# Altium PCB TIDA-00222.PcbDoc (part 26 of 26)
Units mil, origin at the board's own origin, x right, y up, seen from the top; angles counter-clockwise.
Board outline 5049.4 x 2450.97 mil, 2 copper layers (Top Layer, Bottom Layer), stack 62 mil thick; 216 components, 154 nets, 612 pads, 100 vias.

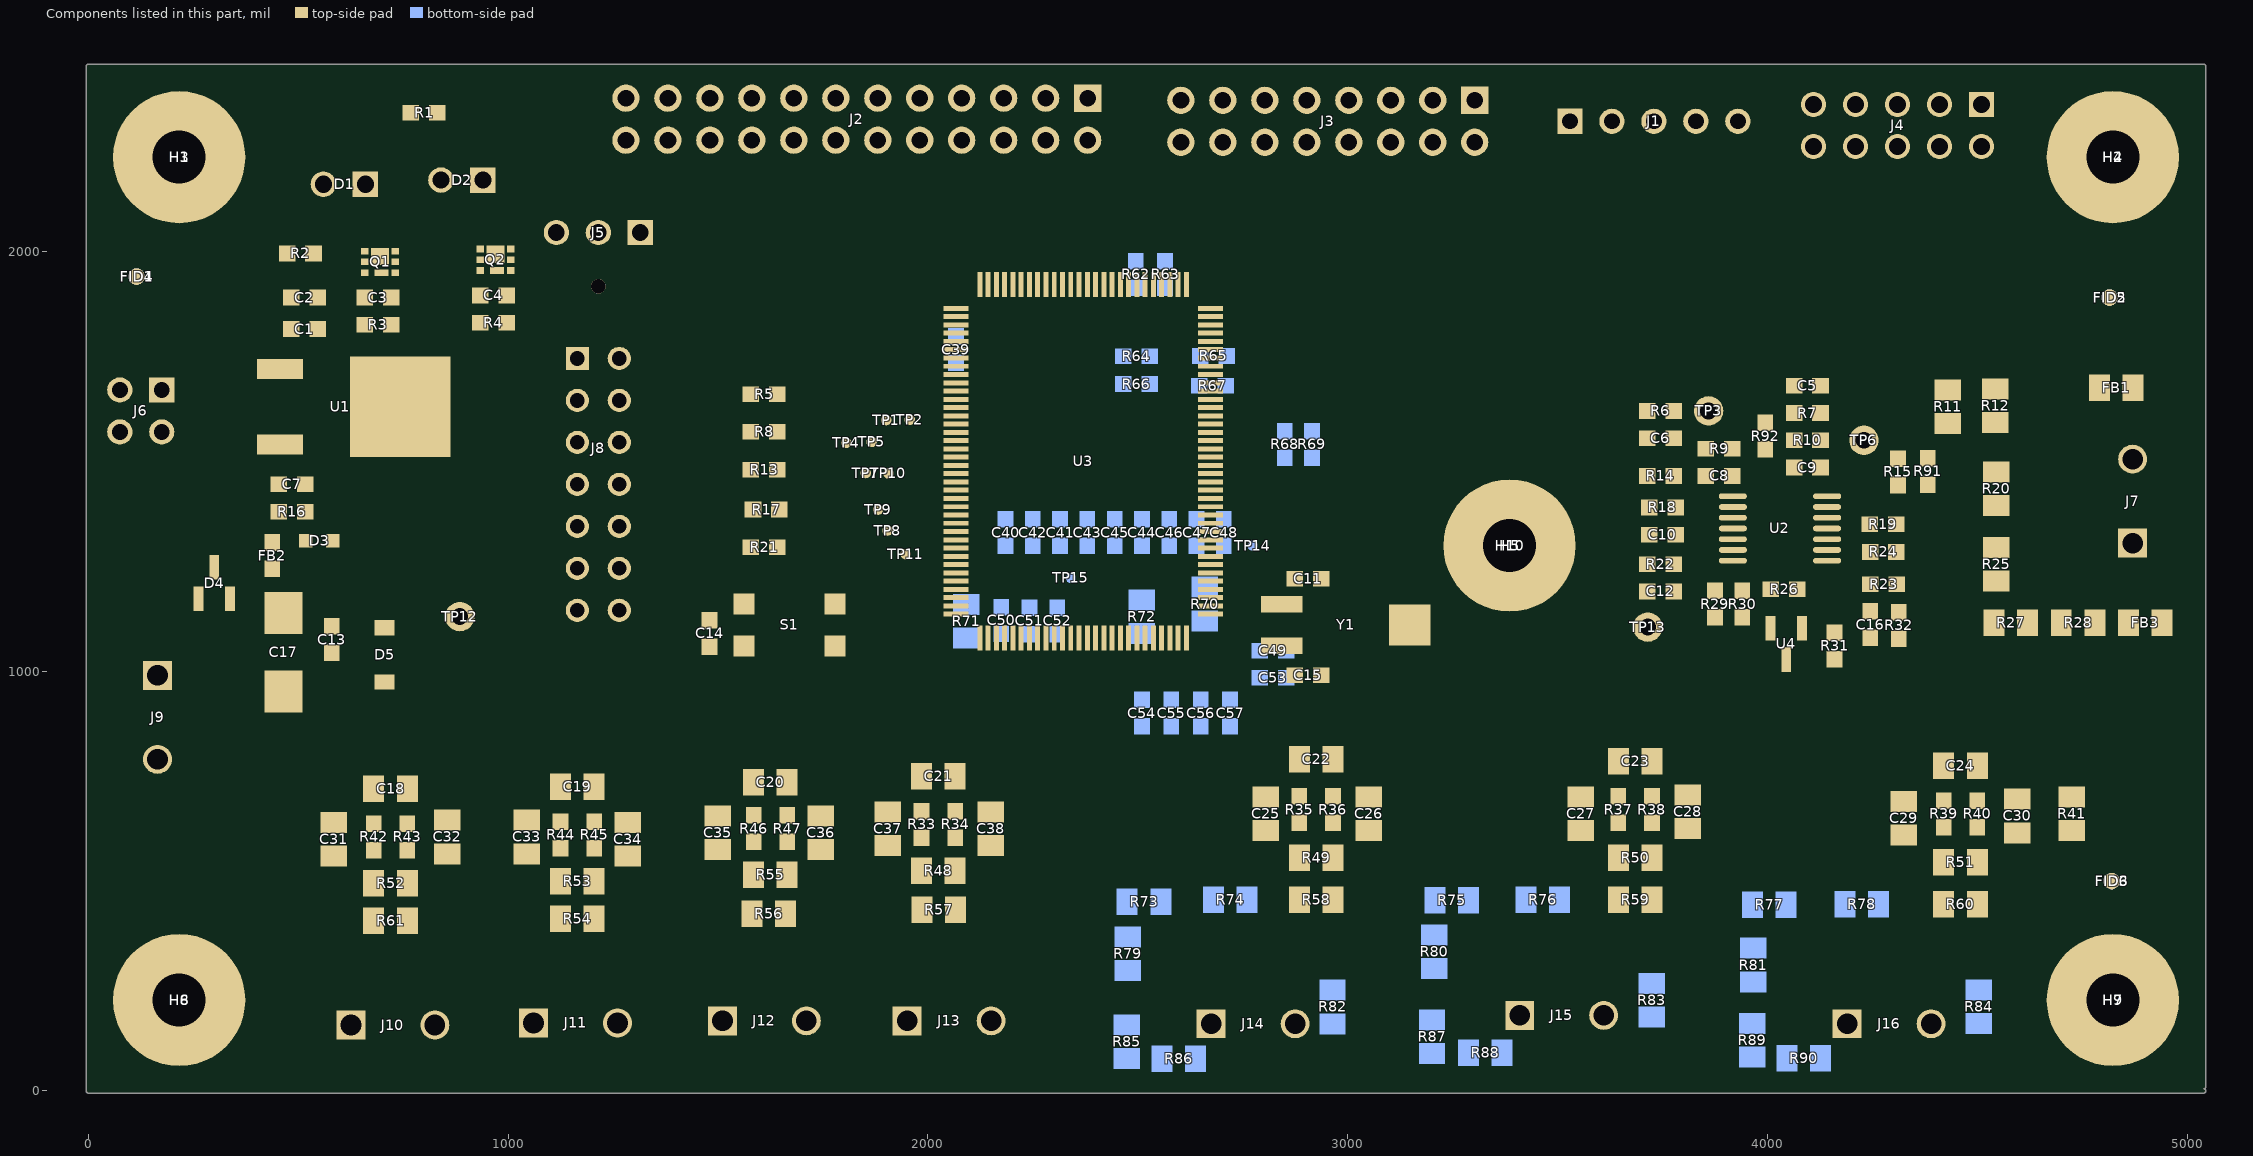
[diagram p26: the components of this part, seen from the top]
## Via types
v1: diameter 40, hole 20, Top Layer to Bottom Layer, tented both sides, 100 vias

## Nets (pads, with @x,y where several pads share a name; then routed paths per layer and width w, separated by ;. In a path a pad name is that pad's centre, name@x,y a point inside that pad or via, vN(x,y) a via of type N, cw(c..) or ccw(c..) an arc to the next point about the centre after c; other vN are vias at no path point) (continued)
pads on no net: D4.2 FID1.1 FID2.1 FID3.1 FID4.1 FID5.1 FID6.1 H1.0 H2.0 H3.1 H4.1 H5.1 H6.0 H7.0 H8.1 H9.1 H10.0 J2.24 J3.16 J8. J8.6 J8.10 J8.12 J8.13 J8.14 U3.4 U3.5 U3.22 U3.23 U3.24 U3.25 U3.28 U3.29 U3.71 U3.72 U3.73 U3.74 U3.75 U3.76 U3.77 U3.78 U3.79 U3.80 U3.81 U3.82 U3.83 U3.84 U3.85 U3.86 U3.87

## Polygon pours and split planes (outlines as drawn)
DGND on Top Layer "Bottom Layer-No Net" (solid, remove dead copper, pour order 23): 530,1800 530,1905 540,1915 545,1920 595,1920 605,1920 620,1905 620,1880 620,1815 620,1805 650,1775 660,1765 770,1765 780,1765 805,1740 825,1720 825,1640 825,1630 805,1610 800,1605 705,1605 535,1775 530,1780 530,1800
DGND on Top Layer "Bottom Layer-No Net" (solid, remove dead copper, pour order 21): 565,1300 565,1370 565,1400 565,1405 560,1410 552.2,1417.8 519,1417.8 512.2,1417.8 500,1430 500,1460 500,1465 510,1475 515,1480 585,1480 600,1480 615,1495 620,1500 620,1615 620,1755 635,1770 735,1770 795,1770 815,1790 825,1800 825,1835 825,1840 810,1855 805,1860 780,1860 775,1860 760,1875 755,1880 755,1910 755,1915 775,1935 840,1935 855,1935 880,1910 890,1900 890,1795 890,1395 800,1305 785,1290 585,1290 575,1290 565,1300
DGND on Top Layer "Bottom Layer-No Net" (solid, remove dead copper, pour order 20): 425,1060 705,1060 755,1060 760,1060 780,1040 795,1025 795,940 795,915 765,885 695,815 435,815 420,815 380,855 375,860 375,1025 375,1038.9 396.1,1060 425,1060
DVCC on Top Layer "Bottom Layer-No Net" (solid, remove dead copper, pour order 18): 410,1265 895,1265 935,1225 955,1205 955,1110 955,1105 935,1085 585,1085 416.1,1085 396.1,1105 390,1111.1 390,1235 390,1250 405,1265 410,1265
NetC7_1 on Top Layer "Bottom Layer-No Net" (solid, remove dead copper, pour order 16): 400,1575 510,1575 515,1575 525,1565 525,1525 525,1520 495,1490 475,1470 475,1440 475,1290 470,1285 415,1285 400,1285 385,1300 385,1365 385,1550 385,1570 390,1575 400,1575
DGND on Top Layer "Bottom Layer-No Net" (solid, remove dead copper, pour order 14): 135,865 220,865 235,850 255,830 255,750 255,745 210,700 205,695 80,695 75,695 35,735 35,880 35,1725 45,1735 95,1735 105,1725 110,1720 110,1705 110,1460 125,1445 175,1445 205,1445 215,1435 220,1430 220,1345 220,1270 135,1185 105,1155 105,1045 105,885 125,865 140,865
NetD2_1 on Top Layer "Bottom Layer-No Net" (solid, remove dead copper, pour order 17): 920,1975 1010,1975 1020,1975 1025,1980 1040,1995 1040,2065 1040,2175 1015,2200 1005,2210 930,2210 910,2210 900,2200 900,2150 900,1990 915,1975 920,1975
NetD1_1 on Top Layer "Bottom Layer-No Net" (solid, remove dead copper, pour order 19): 650,1950 740,1950 750,1950 755,1955 770,1970 770,2040 770,2150 745,2175 735,2185 660,2185 640,2185 630,2175 630,2125 630,1965 645,1950 650,1950
AGND on Bottom Layer "Bottom Layer-No Net" (solid, remove dead copper, pour order 24): 3655,1825 4295,1825 4370,1750 4370,1135 4635,870 4635,600 4630,600 4595,565 4570,590 2365,590 2250,475 2250,115 2190,55 1045,55 1040,60 1035,55 80,55 45,90 45,445 115,515 310,515 565,770 1695,770 2035,1170 2355,1165 2390,1162 2510.86,1160 2590,1045 2730,905 3275,905 3465,1095 3465,1635
DGND on Bottom Layer "Bottom Layer-No Net" (solid, remove dead copper, pour order 22): 2465,1200 2705,960 3260,960 3415,1120 3415,1665 3615,1865 4860,1865 4995,2000 4995,2330 4920,2405 4915,2400 4709,2384 4545,2380 4460,2380 4370,2379 3736,2377 2527,2369 122,2357 50.21,2314.81 40,2285 39,2099 40,1876 41,1663 41,1449 40,1017 42,598 80,565 275,565 530,820 1615,820 1995,1200

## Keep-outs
Keep-Out Layer:
  lines w10: 0,2000 0,0 3780,0 ; 0,2440.94 5039.37,2440.94 ; 5039.37,10 5039.37,2010
Multi-Layer:
  circle w10: c216.54,216.54 r214.85
  circle w10: c216.54,2224.41 r214.85
  circle w10: c4822.83,2224.41 r214.85
  circle w10: c4822.83,216.54 r214.85
  circle w10: c3385.83,1299.21 r196.85

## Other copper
Top Layer:
  text ".Layer_Name" at 577,-858.49 h60
Bottom Layer:
  pour cut-out: 4025,2361 4059.22,2361 4058,2359.78 4058,2337 4034,2337
  pour cut-out: 3964,2361 4040,2361 4047.51,2353.49 4047.51,2338.82 3964.18,2338.82 3964,2339
  pour cut-out: 429,108 438,99 438,51 399,51 394,56 395,57 395,99 404,108
  pour cut-out: 34,523 115,523 125,513 125,418 85,378 36,378 26,388 35,397 35,520
  pour cut-out: 450.74,2277.87 450.74,2375.74 451,2376 409,2376 409,2278 411,2276 412.87,2277.87
  pour cut-out: 1643.8,1797.24 1649,1802.44 1649,1810 1679,1810 1684,1805 1684,1757.05 1684.05,1757 1662,1757 1643.8,1775.2
  pour cut-out: 2295.44,1858.97 2298,1861.53 2298,1933 2254,1933 2250,1929 2251,1928 2251,1870 2284.41,1870
  text ".Layer_Name" at 577,-858.49 h60

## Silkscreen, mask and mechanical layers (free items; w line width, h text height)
Top Overlay:
  circle w10: c2804,1195 r2.24
  circle w8: c3093,1856 r63
  circle w10: c235,1135 r1
  circle w10: c1527,1016 r2
  circle w10: c3868,1417 r1.41
  circle w10: c4114,1125 r5
  lines w6: 501,1215 528,1215 ; 514,1202 514,1225 ; 3646,1707 3646,1673 3659,1660 3659,1656 ; 3925,1700 3925,1575 ; 3944.98,1492.2 3947.2,1492.2 ; 4110,1195 4127,1195 ; 4115,1740 4130,1725 ; 4130,1905 4130,1725 ; 4145,1740 4130,1725 ; 4340,1365 4360,1385 4385,1385 ; 3925,1575 3915,1585 3935,1585 3925,1575 ; 3646,1722 3672,1696 3802,1696 3821,1715 3821,2107 3797,2131 3656,2131 3646,2121 3646,1722 ; 3656,1168 3678,1146 3802,1146 3820,1164 3820,1655 3806,1669 3676,1669 3656,1649 3656,1168
  lines w7.87: 1625,548 1775,548
  lines w9: 3051.5,1898.5 3135.5,1814.5
  text "TIDA-00222" at 2550,2045 h50
  text "ISE3004 REV E1" at 2750,1950 h50
  text "PB" at 3054,1832 h50
  text ".Layer_Name" at 577,-858.49 h60
Bottom Overlay:
  text ".Layer_Name" at 577,-858.49 h60
Top Paste:
  text ".Layer_Name" at 577,-858.49 h60
Bottom Paste:
  text ".Layer_Name" at 577,-858.49 h60
Top Solder:
  text ".Layer_Name" at 577,-858.49 h60
  text ".Layer_Name" at 577,-858.49 h60
Bottom Solder:
  text ".Layer_Name" at 577,-858.49 h60
Drill Guide:
  text ".Layer_Name" at 577,-858.49 h60
M1 Board Outline:
  lines w10: 5039.37,0 0,0 0,2440.94 5039.37,2440.94 5039.37,10
  text ".Layer_Name" at 585,-850 h60
M2 Board Dimensions:
  rectangle: 124.5,-410.5 499.5,-285.5
  rectangle: -0.5,-285.5 124.5,-160.5
  lines w7: -0.5,-285.5 999.5,-285.5 ; 124.5,-410.5 124.5,-160.5 ; 249.5,-410.5 249.5,-160.5 ; 499.5,-410.5 499.5,-160.5 ; 749.5,-410.5 749.5,-160.5 ; -0.5,-410.5 -0.5,-160.5 999.5,-160.5 999.5,-410.5 -0.5,-410.5
  lines w10: -0.5,-475.5 -0.5,-455.5 ; 59.5,-485.5 -0.5,-465.5 ; 59.5,-445.5 -0.5,-465.5 ; 223.58,-465.5 -0.5,-465.5 ; 775.42,-465.5 999.5,-465.5 ; 939.5,-485.5 999.5,-465.5 ; 939.5,-445.5 999.5,-465.5 ; 999.5,-475.5 999.5,-455.5
  text "1000 (mil)" at 233.58,-501.49 h60
M3 3D STEP Top:
  text ".Layer_Name" at 577,-858.49 h60
M4 3D STEP Bottom:
  text ".Layer_Name" at 577,-858.49 h60
M5 Assembly Top:
  circle w10: c4082.5,1149 r4.27
  circle w10: c342,1723 r7.21
  circle w10: c234,1168 r2.83
  circle w10: c1558,994 r7.07
  circle w10: c2442,2365 r4
  circle w10: c3366,2363 r6.32
  lines w6: 495,1193 523,1193 ; 509,1178 509,1207
  lines w10: -292,-930.17 6308,-930.17 ; -292,-726.83 6310,-726.83 ; -292,-523.5 -292,-1133.5 3713,-1133.5 6310,-1133.5 6310,-523.5 -291.5,-523.5 -291.5,-1133.5 1284,-1133.5 ; 2173,-1133.5 2173,-523.5 ; 3748,-726.83 3748,-523.5 ; 4280,-726.83 4280,-523.5 ; 4902,-1140 4902,-937.17
  text "COMPONENTS MARKED 'DNP' SHOULD NOT BE POPULATED." at 1153.5,-318.5 h60
  text "ASSEMBLY VARIANT:" at 1153,-434 h60
  text ".VariantName" at 2189,-434 h60
  text ".prj_number" at 2710,-655 h60
  text "REV:" at 3795,-655 h60
  text "PCB VIEWED FROM TOP SIDE" at -228.5,-655.67 h60
  text "BOARD #:" at 2248,-655.67 h60
  text "SVN REV:" at 4476,-655.67 h60
  text ".VersionControl_RevNumber" at 4982,-655.67 h60
  text "E1" at 4038,-657 h60
  text "Top Assembly" at 575,-857 h60
  text "PLOT NAME =" at -228.5,-1064.34 h60
  text ".plot_File_Name" at 577,-1064.34 h60
  text "GENERATED    :" at 2250,-1064.34 h60
  text ".Print_Date" at 3119.5,-1064.34 h60
  text ".Print_Time" at 3848.5,-1064.34 h60
  text "TEXAS INSTRUMENTS" at 5113,-1064.34 h60
M6 Assembly Bottom:
  lines w10: -292.5,-727.33 6309.5,-727.33 ; -290.5,-930.67 6309.5,-930.67 ; 1115.5,-1140.5 1115.5,-937.67 ; 1737.5,-727.33 1737.5,-524 ; 2174,-726.83 2174,-523.5 ; 3844.5,-1134 3844.5,-524 ; 4733.5,-1134 6309,-1134 6309,-524 -292.5,-524 -292.5,-1134 2304.5,-1134 6309.5,-1134 6309.5,-524
  text "COMPONENTS MARKED 'DNP' SHOULD NOT BE POPULATED." at 6102,-318 h60
  text ".VariantName" at 5058,-434 h60
  text "ASSEMBLY VARIANT:" at 6097,-434 h60
  text "REV:" at 2111,-652 h60
  text ".VersionControl_RevNumber" at 1035.5,-656.17 h60
  text "SVN REV:" at 1541.5,-656.17 h60
  text "TIDA-00222" at 3224,-656.17 h60
  text "BOARD #:" at 3769.5,-656.17 h60
  text "PCB VIEWED FROM BOTTOM SIDE" at 6246,-656.17 h60
  text "E1" at 1887,-659 h60
  text "Bottom Assembly" at 2297,-858 h60
  text "TEXAS INSTRUMENTS" at 904.5,-1064.84 h60
  text ".Print_Time" at 2169,-1064.84 h60
  text ".Print_Date" at 2898,-1064.84 h60
  text "GENERATED    :" at 3767.5,-1064.84 h60
  text ".plot_File_Name" at 5440.5,-1064.84 h60
  text "PLOT NAME =" at 6246,-1064.84 h60
M9 Title Sheet:
  drawing of 57 lines, arcs and shapes, not listed
  text "1" at 739.84,8036.5 h70
  text "2" at 3235.5,8036.5 h70
  text "3" at 5724.84,8036.5 h70
  text "4" at 8231.51,8036.5 h70
  text "5" at 10730.5,8036.5 h70
  text "6" at 13235.5,8036.5 h70
  text "A" at -416.5,6893.5 h70
  text "A" at 14383.5,6893.5 h70
  text "B" at -416.5,4513.5 h70
  text "B" at 14383.5,4513.5 h70
  text "C" at -416.5,2138.5 h70
  text "C" at 14383.5,2138.5 h70
  text "PROJECT TITLE:" at 11343.5,277.5 h45
  text "TIDA00222 - ISE3004" at 11393.5,144.17 h70
  text "DESIGNED FOR:" at 11343.5,-23.5 h45
  text ".PRJ_Customer" at 11393.5,-163.5 h70
  text "D" at -416.5,-231.5 h70
  text "D" at 14383.5,-231.5 h70
  text "FILE NAME:" at 11343.5,-323.5 h45
  text "TIDA00222" at 11698,-429 h70
  text "Texas Instruments (TI) and/or its licensors do not warrant the accuracy or completeness of this specification" at 6374,-605.34 h45
  text "ENGINEER:" at 11343.5,-613.5 h45
  text "LAYOUT BY:" at 12848.5,-613.5 h45
  text "or any information contained therein. TI and/or its licensors do not warrant that this design will meet" at 6329.01,-718 h45
  text ".PRJ_Engineer" at 11393.5,-768.49 h70
  text ".PCB_Layout" at 12899,-768.49 h40
  text "the specifications, will be suitable for your application or fit for any particular purpose, or will operate in" at 6329.01,-830.67 h45
  text "ALTIUM DESIGNER VERSION:" at 12848.5,-923.5 h45
  text "an implementation. TI and/or its licensors do not warrant that the design is production worthy. You should" at 6329.01,-943.33 h45
  text "completely validate and test your design implementation to confirm the system functionality for your application." at 6374,-1056 h45
  text ".print_Scale" at 11393.5,-1056.83 h70
  text ".Application_BuildNumber" at 12899,-1056.83 h70
  text "1" at 739.84,-1263.5 h70
  text "2" at 3235.5,-1263.5 h70
  text "3" at 5724.84,-1263.5 h70
  text "4" at 8231.51,-1263.5 h70
  text "5" at 10730.5,-1263.5 h70
  text "6" at 13235.5,-1263.5 h70
M10 Fab Notes:
  drawing of 212 lines, arcs and shapes, not listed
  text "DESIGN INFORMATION" at 12381.02,6810 h60
  text "(REFER ALSO ARRAY/PANEL PROFILING INFORMATION)" at 12019.46,6648.29 h60
  text "BOARD SIZE" at 11333.46,6644 h60
  text "62MM" at 11795.78,6516.18 h60
  text "X" at 12301.46,6516.18 h60
  text "128MM" at 12532.78,6516.18 h60
  text "Number of Layers :" at 11731.46,6416 h60
  text "2" at 12826.27,6406 h60
  text "MIN. TRACK WIDTH:" at 11731.46,6277 h60
  text "10" at 12827.7,6277 h60
  text "MIL" at 12982.46,6277 h60
  text "MIL" at 13005,6152 h60
  text "MIN. CLEARANCE:" at 11731.46,6145 h60
  text "7.8" at 12827.7,6145 h60
  text "MIN. VIA PAD SIZE:" at 11731.46,6013 h60
  text "40" at 12797.71,6013 h60
  text "MIL" at 12982.46,6013 h60
  text "0.19mm (7.5MIL)" at 12426.46,5871.29 h60
  text "MINIMUM ANNULAR RING" at 11402.23,5867 h60
  text "EXTERNAL" at 13134.46,5867 h60
  text "PER" at 11602.23,5749 h60
  text "IPC-D-275 CLASS 2 LEVEL C" at 11822.23,5749 h60
  text "MIL, HOLES" at 13310.46,5636.71 h60
  text "+/-" at 12918,5636 h60
  text "+/-" at 13772,5636 h60
  text "REGISTRATION TOLERANCES:" at 11402.23,5631 h60
  text "METAL" at 12602,5631 h60
  text "5" at 13178.2,5631 h60
  text "3" at 14011.2,5631 h60
  text "MIL" at 14127.46,5631 h60
  text "VIA'S ARE TENTED" at 11634.46,5514 h60
  text "MATERIAL:" at 11332.46,5324.54 h60
  text "FR-4 High Tg" at 12318.9,5184.21 h60
  text "FR-408" at 11753.46,5175.64 h60
  text "X" at 12165.46,5175.64 h60
  text "OTHER" at 13241.46,5175.64 h60
  text "63 MIL (1.6mm) +/-10%" at 12073.56,5012.92 h60
  text "THICKNESS:" at 11407.23,5008.64 h60
  text "X" at 11945.4,5008.64 h60
  text "OTHER" at 13358.46,5008.64 h60
  text "TOLERANCE:" at 11407.23,4850.64 h60
  text "X" at 12246.53,4850.64 h60
  text "ANSI IPC-6012 TYPE 3 CLASS 2" at 12433.48,4850.64 h60
  text "OTHER +/-" at 12433.46,4694.64 h60
  text "BOW & TWIST:" at 11407.23,4537.64 h60
  text "X" at 12246.53,4537.64 h60
  text "ANSI IPC-6012 TYPE 3 CLASS 2" at 12433.48,4537.64 h60
  text "OTHER +/-" at 12433.46,4379.13 h60
  text "COPPER THICKNESS (FINISHED):" at 11332.46,4243.64 h60
  text "1.4MIL (1oz)" at 12212.46,4090.92 h60
  text "2MIL (1.4oz)" at 12979.46,4090.92 h60
  text "2.8MIL (2oz)" at 13706.46,4090.92 h60
  text "OUTER:" at 11689.46,4086.64 h60
  text "X" at 12084,4086 h60
  text "1.4MIL (1oz)" at 12212.46,3933.92 h60
  text "2.8MIL (2oz)" at 12979.46,3933.92 h60
  text "N/A" at 13706,3934.29 h60
  text "INNER SIGNAL:" at 11400.38,3929.64 h60
  text "DRILLING:" at 11332.46,3790.64 h60
  text "REFERENCE:" at 11407.23,3673.64 h60
  text "X" at 12055.46,3673.64 h60
  text "AS SHOWN" at 12242.46,3673.64 h60
  text "X" at 12956.46,3673.64 h60
  text "NC_DRILL FILES" at 13093.46,3673.64 h60
  text "PTH MIN COPPER THICKNESS:" at 11407.23,3515.64 h60
  text "X" at 12757.46,3515.64 h60
  text "1MIL" at 12894.46,3515.64 h60
  text "OTHER" at 13391.46,3515.64 h60
  text "BOARD FINISH:" at 11332.46,3356.64 h60
  text "SILKSCREEN:" at 11487.68,3238.64 h60
  text "X" at 12436.46,3238.64 h60
  text "TOP" at 12562.46,3238.64 h60
  text "X" at 12946.46,3238.64 h60
  text "BOTTOM" at 13073.46,3238.64 h60
  text "SILKSCREEN COLOR:" at 11487.68,3071.64 h60
  text "X" at 12435.42,3071.64 h60
  text "WHITE" at 12562.46,3071.64 h60
  text "OTHER" at 13073.46,3071.64 h60
  text "SOLDER RESIST COLOR:" at 11487.68,2901.64 h60
  text "X" at 12055.42,2742.44 h60
  text "GREEN" at 12182.46,2742.44 h60
  text "BLUE" at 12773.46,2742.44 h60
  text "OTHER" at 13311.46,2742.44 h60
  text "IMMERSION GOLD (ENIG)" at 12393.46,2553.92 h60
  text "ENEPIG" at 13731,2550.64 h60
  text "SURFACE FINISH:" at 11332.46,2549.64 h60
  text "X" at 12206.51,2549.64 h60
  text "IMM. TIN/SILVER OR EQUIV" at 11662,2392.64 h60
  text "OTHER" at 13093.46,2392.64 h60
  text "ARRAY/PANEL:" at 11332.46,2213.64 h60
  text "CUT AND TRIM PER MECH LAYER 1" at 12393.46,2209.35 h60
  text "N.C. ROUTE" at 12393.46,2057.64 h60
  text "X" at 13072.46,2057.64 h60
  text "V. SCORE" at 13259.46,2057.64 h60
  text "CERTIFICATION:" at 11332.46,1920.64 h60
  text "MATERIALS AND WORKMANSHIP FOR ALL PCBS" at 12057.46,1920.64 h60
  text "TO MEET OR EXCEED THE REQUIREMENTS OF:" at 12057.46,1822.64 h60
  text "X" at 11683.96,1686.13 h60
  text "ANSI IPC-A-600F CLASS ->" at 11822.96,1686.13 h60
  text "X" at 13462.02,1686.13 h60
  text "2" at 13580.96,1686.14 h60
  text "1" at 13265.96,1684.64 h60
  text "3" at 13934.96,1684.64 h60
  text "X" at 11686.02,1526.64 h60
  text "UL 94V-0" at 11822.96,1526.64 h60
  text "X" at 12498.02,1526.64 h60
  text "RoHS" at 12634.96,1526.64 h60
  text "OTHER" at 13279.36,1526.64 h60
  text "PER ORDER" at 13676.42,1526.64 h60
  text "ADDITIONAL REQUIREMENTS:" at 11332.46,1385.64 h60
  text "MICROSECTION:" at 11407.23,1270.64 h60
  text "YES" at 12312.96,1270.64 h60
  text "REQUIRED" at 13174.46,1114.49 h60
  text "BARE BOARD ELEC. TEST:" at 11407.23,1111.64 h60
  text "NONE" at 12712.96,1111.64 h60
  text "X" at 13047.46,1111.64 h60
  text "PER ORDER" at 13766.46,1111.64 h60
  text "MANUFACTURER'S UL:" at 11407.23,954.64 h60
  text "RAIL" at 12572.96,950.35 h60
  text "METAL" at 13064.77,950.35 h60
  text "X" at 13440,950 h60
  text "SILK" at 13576.46,950.35 h60
M11 Gerber Information:
  lines w10: -292,-930.17 6308,-930.17 ; -292,-726.83 6310,-726.83 ; -292,-523.5 -292,-1133.5 3713,-1133.5 6310,-1133.5 6310,-523.5 ; -291.5,-530 6310,-530 ; -291.5,-523.5 -291.5,-1133.5 1284,-1133.5 ; 2173,-1133.5 2173,-523.5 ; 3745,-728.33 3745,-525 ; 4280,-726.83 4280,-523.5 ; 4902,-1140 4902,-937.17
  text "REV:" at 3795,-654 h60
  text "TIDA-00222" at 2710,-655 h60
  text "ALL ARTWORK VIEWED FROM TOP SIDE" at -228.5,-655.67 h60
  text "BOARD #:" at 2248,-655.67 h60
  text "SVN REV:" at 4476,-655.67 h60
  text ".VersionControl_RevNumber" at 4982,-655.67 h60
  text "E1" at 4040,-659 h60
  text "LAYER NAME =" at -228.5,-858.49 h60
  text "PLOT NAME =" at -228.5,-1064.34 h60
  text ".plot_File_Name" at 577,-1064.34 h60
  text "GENERATED    :" at 2250,-1064.34 h60
  text ".Print_Date" at 3119.5,-1064.34 h60
  text ".Print_Time" at 3848.5,-1064.34 h60
  text "TEXAS INSTRUMENTS" at 5113,-1064.34 h60
M12 Stackup:
  lines w6: 11360,7460 13910,7460 ; 11360,7564.4 13910,7564.4 ; 11300,6975 ccw(c11334,6975) 11334,6941 13936,6941 ccw(c13936,6975) 13970,6975 13970,7681 ccw(c13936,7681) 13936,7715 11334,7715 ccw(c11334,7681) 11300,7681 11300,6975
  text "The Stackup Legend below this is static." at 11605.5,7874.5 h60
  text "If you change the stackup, update the Legend." at 11615.5,7784.5 h60
  text "Layer Stack Up Detail for: Ref_Design.PcbDoc" at 11360,7597.1 h57
  text "Layer" at 11360,7525.4 h30
  text "Gerber" at 12255.81,7525.4 h30
  text "Copper" at 12819.33,7525.4 h30
  text "Dielectric" at 13422.04,7525.4 h30
  text "Name" at 11360,7477.4 h30
  text "Document" at 12255.81,7477.4 h30
  text "Thickness" at 12819.33,7477.4 h30
  text "Material" at 13422.04,7477.4 h30
  text "Top Solder Mask" at 11360,7384.44 h34
  text "(.GTS)" at 12255.81,7384.44 h34
  text "Solder Resist" at 13422.04,7384.44 h34
  text "Top Layer" at 11360,7287.69 h34
  text "(.GTL)" at 12255.81,7287.69 h34
  text "1.4mil" at 12819.33,7287.69 h34
  text "FR-4" at 13422.04,7239.31 h34
  text "Bottom Layer" at 11360,7190.94 h34
  text "(.GBL)" at 12255.81,7190.94 h34
  text "1.4mil" at 12819.33,7190.94 h34
  text "Bottom Solder Mask" at 11360,7094.19 h34
  text "(.GBS)" at 12255.81,7094.19 h34
  text "Solder Resist" at 13422.04,7094.19 h34
M13 Component Bodies Top:
  text ".Layer_Name" at 577,-858.49 h60
  text ".Layer_Name" at 577,-858.49 h60
M14 Component Bodies Bottom:
  text ".Layer_Name" at 577,-858.49 h60
M15 Courtyards Top:
  text ".Layer_Name" at 577,-858.49 h60
M16 Courtyards Bottom:
  text ".Layer_Name" at 577,-858.49 h60
Drill Drawing:
  text ".legend" at 5510,955 h60
  text "Drill Table" at 5525,815 h60
  text ".Layer_Name" at 577,-858.49 h60

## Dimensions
0,0 to 0,2440.94 on Drill Drawing
0,2440.94 to 5039.37,2440.94 on Drill Drawing
4822.83,216.54 to 4822.83,2224.41 on M2 Board Dimensions
216.54,2224.41 to 4822.83,2224.41 on M2 Board Dimensions
3385.83,1299.21 to 4822.83,2224.41 on M2 Board Dimensions
3385.83,1299.21 to 4822.83,2224.41 on M2 Board Dimensions
3385.83,1299.21 to 4822.83,216.54 on M2 Board Dimensions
